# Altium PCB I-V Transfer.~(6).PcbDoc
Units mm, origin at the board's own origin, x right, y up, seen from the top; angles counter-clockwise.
Board outline 152.4 x 101.6 mm, 2 copper layers (Top Layer, Bottom Layer); 23 components, 15 nets, 67 pads, 0 vias.
Unrouted connection lines stored in the file: 44.

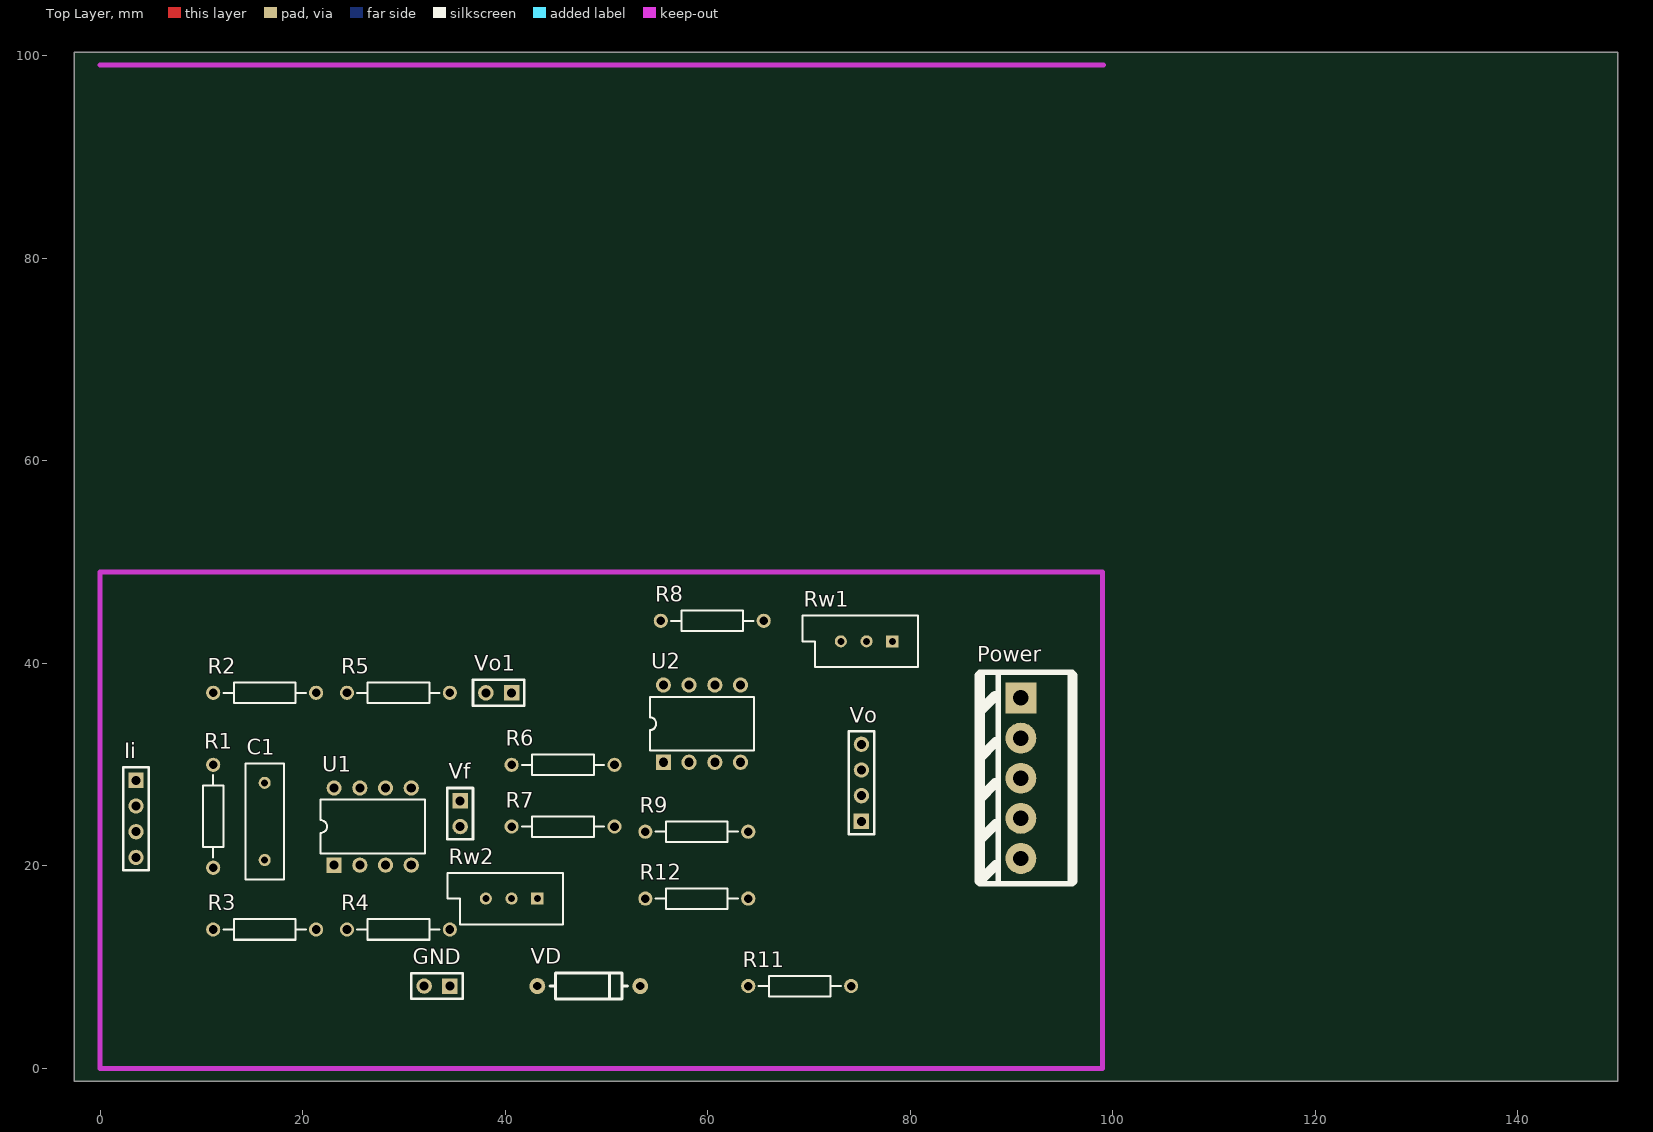
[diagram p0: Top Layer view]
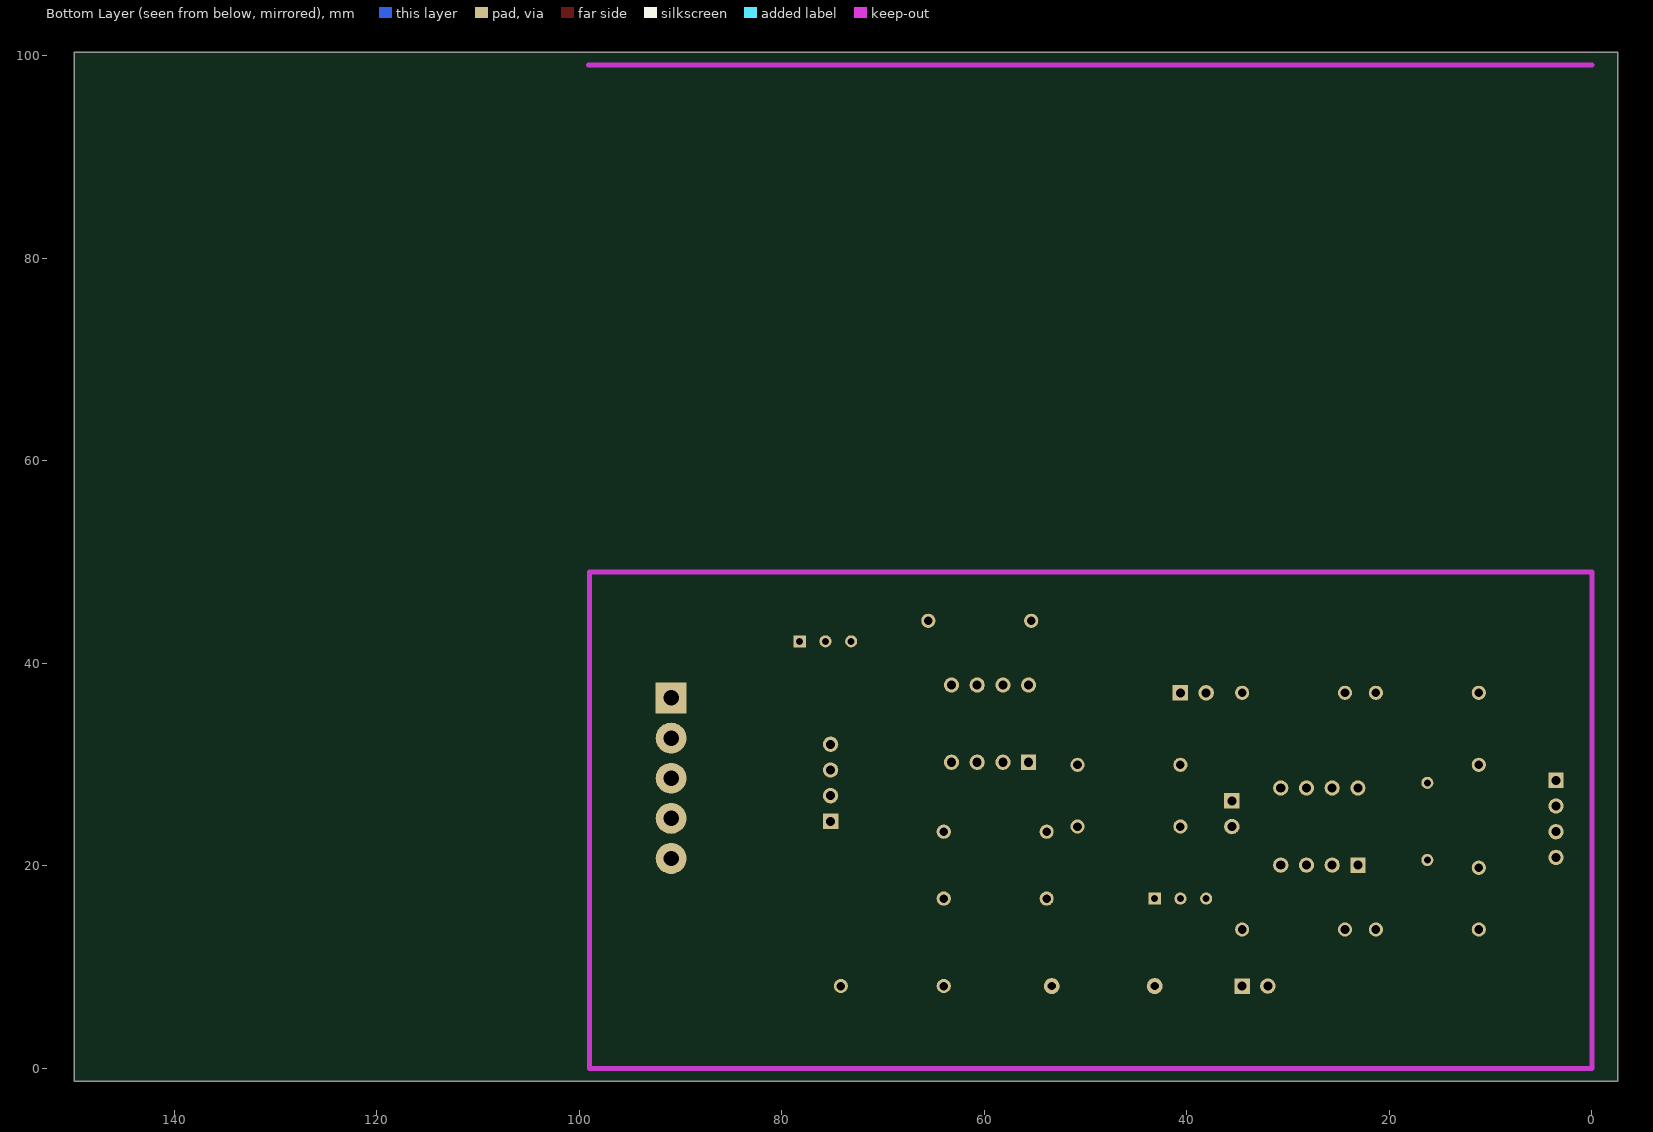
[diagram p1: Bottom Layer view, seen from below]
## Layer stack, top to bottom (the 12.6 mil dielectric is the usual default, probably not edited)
Top Layer: signal copper 0.0356
Dielectric: dielectric 0.32, FR-4, Dk 4.8
Bottom Layer: signal copper 0.0356

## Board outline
-2.54,-1.27 149.86,-1.27 149.86,100.33 -2.54,100.33

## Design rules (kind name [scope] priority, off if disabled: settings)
Clearance [All] p1 off: gap=0.254
DiffPairsRouting [All] p1 off: maxlimit=0.254 minlimit=0.254 mostfreqgap=0.254 maxuncoupledlength=12.7
FanoutControl Fanout_BGA [IsBGA] p1 off: bgadir=Out bgaviamode=Centered fanoutstyle=Auto fanoutdirection=Alternating viagrid=0.025 // Fanout_BGA (Default Rule)
FanoutControl Fanout_LCC [IsLCC] p2 off: bgadir=Out bgaviamode=Centered fanoutstyle=Auto fanoutdirection=Alternating viagrid=0.025 // Fanout_LCC (Default Rule)
FanoutControl Fanout_SOIC [IsSOIC] p3 off: bgadir=Out bgaviamode=Centered fanoutstyle=Auto fanoutdirection=Alternating viagrid=0.025 // Fanout_SOIC (Default Rule)
FanoutControl Fanout_Small [(CompPinCount < 5)] p4 off: bgadir=Out bgaviamode=Centered fanoutstyle=Auto fanoutdirection=OutThenIn viagrid=0.025 // Fanout_Small (Default Rule)
FanoutControl Fanout_Default [All] p5 off: bgadir=Out bgaviamode=Centered fanoutstyle=Auto fanoutdirection=Alternating viagrid=0.025 // Fanout_Default (Default Rule)
HoleSize [All] p1 off: absolutevalues=TRUE maxlimit=2.54 minlimit=0.025 maxpercent=80.000 minpercent=20.000
HoleToHoleClearance [All] p1 off: gap=0.254 allowstackedmicrovias=TRUE
LayerPairs [All] p1 off: enforce=TRUE
MinimumSolderMaskSliver [All] p1 off: minsoldermaskwidth=0.254
NetAntennae [All] p1 off: netantennaetolerance=0
PolygonConnect [All] p1: connectstyle=Relief reliefconductorwidth=0.254 reliefentries=4 polygonreliefangle="90 Angle"
RoomDefinition "I-V Transfer" [InComponentClass('I-V Transfer')] p1: confinementstyle=ConfineIn formatcopy=TRUE lockcomponents=FALSE outline 5.08,63.5 135.255,63.5 135.255,88.265 5.08,88.265
RoutingCorners [All] p1 off: cornerstyle=45-Degree minsetback=2.54 maxsetback=2.54
RoutingLayers [All] p1 off: top layer_v5=TRUE bottom layer_v5=TRUE
RoutingPriority [All] p1 off: routingpriority=0
RoutingTopology [All] p1 off: topology=Shortest
RoutingVias [All] p1 off: holewidth=0.711 width=1.27 viastyle="Through Hole" minholewidth=0.711 minwidth=1.27 maxholewidth=0.711 maxwidth=1.27
ShortCircuit [All] p1 off: allowed=FALSE
SilkToSilkClearance [All] p1 off: silktosilkclearance=0.254
SilkscreenOverComponentPads [All] p1 off: minsilkscreentomaskgap=0.254
SolderMaskExpansion [All] p1: expansion=0.102
TestPointUsage [All] p1 off: valid=0 allowmultiple=FALSE
Testpoint [All] p1 off: side=15 testpointundercomponent=TRUE minsize=1.016 maxsize=2.54 preferedsize=1.524 minholesize=0 maxholesize=1.016 preferedholesize=0.813 testpointgrid=0.025 style=1023 order=0-112345678
UnRoutedNet [All] p1 off:
Width [All] p1 off: maxlimit=1.27 minlimit=0.254 preferedwidth=0.254
5 further rules are at their usual default settings.

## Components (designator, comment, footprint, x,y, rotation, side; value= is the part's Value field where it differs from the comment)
C1 "Cap" RAD-0.3 16.256,24.384 r90 top
GND "Header 2" SIP-2 34.544,8.128 r180 top
Ii "Header 4" SIP-4 3.556,28.448 r270 top
Power "Header 5" "POWER PLUG5" 90.932,36.576 r90 top
R1 "Res2" AXIAL-0.4 11.176,24.892 r90 top
R2 "Res2" AXIAL-0.4 16.256,37.084 r0 top
R3 "Res2" AXIAL-0.4 16.256,13.716 r0 top
R4 "Res2" AXIAL-0.4 29.464,13.716 r180 top
R5 "Res2" AXIAL-0.4 29.464,37.084 r0 top
R6 "Res2" AXIAL-0.4 45.72,29.972 r0 top
R7 "Res2" AXIAL-0.4 45.72,23.876 r0 top
R8 "Res2" AXIAL-0.4 60.452,44.196 r180 top
R9 "Res2" AXIAL-0.4 58.928,23.368 r180 top
R11 "Res2" AXIAL-0.4 69.088,8.128 r180 top
R12 "Res2" AXIAL-0.4 58.928,16.764 r180 top
Rw1 "RPot" VR5 75.692,42.164 r180 top
Rw2 "RPot" VR5 40.64,16.764 r180 top
U1 "OP-07" DIP-8 26.924,23.876 r0 top
U2 "OP-07" DIP-8 59.436,34.036 r0 top
VD "5.1V" DIODE0.4 43.18,8.128 r0 top
Vf "Header 2" SIP-2 35.56,26.416 r270 top
Vo "Header 4" SIP-4 75.184,24.384 r90 top
Vo1 "Header 2" SIP-2 40.64,37.084 r180 top

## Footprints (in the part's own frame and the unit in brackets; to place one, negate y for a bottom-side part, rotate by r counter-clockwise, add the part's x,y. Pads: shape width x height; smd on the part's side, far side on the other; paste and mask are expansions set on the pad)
AXIAL-0.4 [mm] "Resistor; 2 Leads"
  round 1.4 hole 0.85: 1(-5.08,0) 2(5.08,0)
  silkscreen extent -4.06,-1.02 4.06,1.02
DIODE0.4 [mil]
  round 62 hole 32: 1(0,0) 2(400,0)
  silkscreen extent 50,-50 350,50
DIP-8 [mm] "DIP; 8 Leads; Row Spacing 7.62 mm; Pitch 2.54 mm"
  rect 1.5x1.5 hole 0.9: 1(-3.81,-3.81)
  round 1.5 hole 0.9: 2(-1.27,-3.81) 3(1.27,-3.81) 4(3.81,-3.81) 5(3.81,3.81) 6(1.27,3.81) 7(-1.27,3.81) 8(-3.81,3.81)
  silkscreen extent -5.15,-2.65 5.15,2.65
"POWER PLUG5" [mil] "双电源插座"
  rect 120x120 hole 60: 1(0,0)
  round 120 hole 60: 2(-156,0) 3(-312,0) 4(-468,0) 5(-624,0)
  silkscreen extent -722,-200 100,160
RAD-0.3 [mm] "Capacitor; 2 Leads"
  round 1.2 hole 0.7: 1(-3.81,0) 2(3.81,0)
  silkscreen extent -5.71,-1.91 5.71,1.91
SIP-2 [mil]
  rect 60x60 hole 35: 1(0,0)
  round 60 hole 35: 2(100,0)
  silkscreen extent -50,-50 150,50
SIP-4 [mil]
  rect 60x60 hole 35: 1(0,0)
  round 60 hole 35: 2(100,0) 3(200,0) 4(300,0)
  silkscreen extent -50,-50 350,50
VR5 [mm] "Potentiometer; 3 Leads"
  rect 1.2x1.2 hole 0.7: 1(-2.54,0)
  round 1.2 hole 0.7: 2(0,0) 3(2.54,0)
  silkscreen extent -5.08,-2.54 6.35,2.54

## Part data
C1: "Capacitor"
GND Vf Vo1: "Header, 2-Pin"
Ii Vo: "Header, 4-Pin"
Power: "Header, 5-Pin"
R1 R2 R3 R4 R5 R6 R7 R8 R9 R11 R12: "Resistor"
Rw1 Rw2: "Potentiometer"
VD: library part "Diode 11DQ03", "Schottky Rectifier"

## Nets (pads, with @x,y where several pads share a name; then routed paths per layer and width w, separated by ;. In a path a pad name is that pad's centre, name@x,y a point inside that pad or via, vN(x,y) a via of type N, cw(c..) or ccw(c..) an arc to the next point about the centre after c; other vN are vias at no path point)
+12V: Power.1 R11.1 U1.7 U2.7
-12V: Power.5 U1.4 U2.4
GND: GND.1 GND.2 Power.3 R4.1 R9.1 Rw2.1 VD.1 Vo.3 Vo.4
NetC1_1: C1.1 Ii.3 Ii.4 R1.1 R3.1
NetC1_2: C1.2 Ii.1 Ii.2 R1.2 R2.1
NetR2_2: R2.2 R5.1 U1.2
NetR3_2: R3.2 R4.2 U1.3
NetR5_2: R5.2 R6.1 U1.6 Vo1.1 Vo1.2
NetR6_2: R6.2 R7.2 R8.1 U2.2
NetR7_1: R7.1 Rw2.2 Vf.1 Vf.2
NetR8_2: R8.2 Rw1.3
NetR9_2: R9.2 U2.3
NetR11_2: R11.2 R12.1 VD.2
NetR12_2: R12.2 Rw2.3
NetRw1_1: Rw1.1 Rw1.2 U2.6 Vo.1 Vo.2
pads on no net: Power.2 Power.4 U1.1 U1.5 U1.8 U2.1 U2.5 U2.8

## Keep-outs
Keep-Out Layer:
  lines w0.508: 0,99.06 99.06,99.06 ; 0,49 99,49 99,0 0,0 0,49 ; 0,49 0,49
